VERSION 5.7 ;
BUSBITCHARS "[]" ;
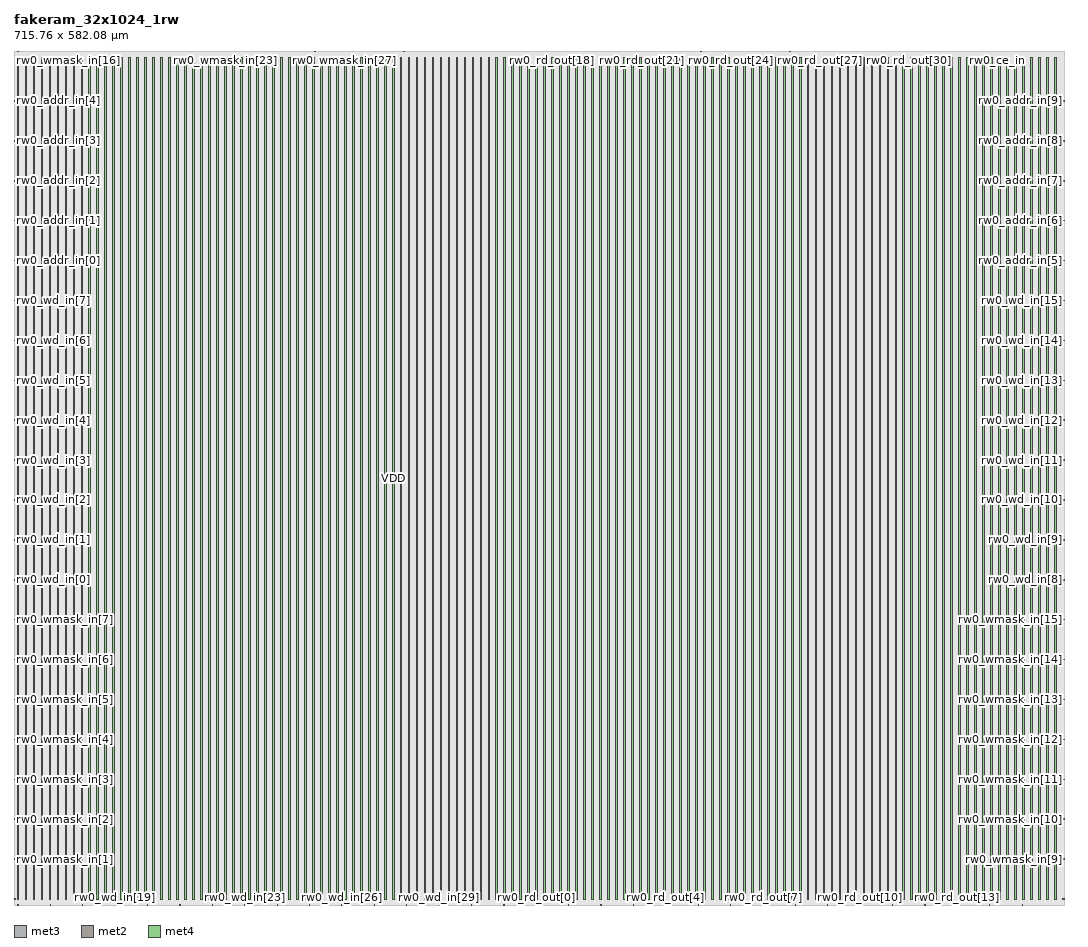
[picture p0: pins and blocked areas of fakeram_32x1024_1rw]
MACRO fakeram_32x1024_1rw
  FOREIGN fakeram_32x1024_1rw 0 0 ;
  SYMMETRY X Y R90 ;
  SIZE 715.760 BY 582.080 ;
  CLASS BLOCK ;
  PIN rw0_wmask_in[0]
    DIRECTION INPUT ;
    USE SIGNAL ;
    SHAPE ABUTMENT ;
    PORT
      LAYER met3 ;
      RECT 0.000 3.930 0.900 4.230 ;
    END
  END rw0_wmask_in[0]
  PIN rw0_wmask_in[1]
    DIRECTION INPUT ;
    USE SIGNAL ;
    SHAPE ABUTMENT ;
    PORT
      LAYER met3 ;
      RECT 0.000 31.130 0.900 31.430 ;
    END
  END rw0_wmask_in[1]
  PIN rw0_wmask_in[2]
    DIRECTION INPUT ;
    USE SIGNAL ;
    SHAPE ABUTMENT ;
    PORT
      LAYER met3 ;
      RECT 0.000 58.330 0.900 58.630 ;
    END
  END rw0_wmask_in[2]
  PIN rw0_wmask_in[3]
    DIRECTION INPUT ;
    USE SIGNAL ;
    SHAPE ABUTMENT ;
    PORT
      LAYER met3 ;
      RECT 0.000 85.530 0.900 85.830 ;
    END
  END rw0_wmask_in[3]
  PIN rw0_wmask_in[4]
    DIRECTION INPUT ;
    USE SIGNAL ;
    SHAPE ABUTMENT ;
    PORT
      LAYER met3 ;
      RECT 0.000 112.730 0.900 113.030 ;
    END
  END rw0_wmask_in[4]
  PIN rw0_wmask_in[5]
    DIRECTION INPUT ;
    USE SIGNAL ;
    SHAPE ABUTMENT ;
    PORT
      LAYER met3 ;
      RECT 0.000 139.930 0.900 140.230 ;
    END
  END rw0_wmask_in[5]
  PIN rw0_wmask_in[6]
    DIRECTION INPUT ;
    USE SIGNAL ;
    SHAPE ABUTMENT ;
    PORT
      LAYER met3 ;
      RECT 0.000 167.130 0.900 167.430 ;
    END
  END rw0_wmask_in[6]
  PIN rw0_wmask_in[7]
    DIRECTION INPUT ;
    USE SIGNAL ;
    SHAPE ABUTMENT ;
    PORT
      LAYER met3 ;
      RECT 0.000 194.330 0.900 194.630 ;
    END
  END rw0_wmask_in[7]
  PIN rw0_wmask_in[8]
    DIRECTION INPUT ;
    USE SIGNAL ;
    SHAPE ABUTMENT ;
    PORT
      LAYER met3 ;
      RECT 714.860 3.930 715.760 4.230 ;
    END
  END rw0_wmask_in[8]
  PIN rw0_wmask_in[9]
    DIRECTION INPUT ;
    USE SIGNAL ;
    SHAPE ABUTMENT ;
    PORT
      LAYER met3 ;
      RECT 714.860 31.130 715.760 31.430 ;
    END
  END rw0_wmask_in[9]
  PIN rw0_wmask_in[10]
    DIRECTION INPUT ;
    USE SIGNAL ;
    SHAPE ABUTMENT ;
    PORT
      LAYER met3 ;
      RECT 714.860 58.330 715.760 58.630 ;
    END
  END rw0_wmask_in[10]
  PIN rw0_wmask_in[11]
    DIRECTION INPUT ;
    USE SIGNAL ;
    SHAPE ABUTMENT ;
    PORT
      LAYER met3 ;
      RECT 714.860 85.530 715.760 85.830 ;
    END
  END rw0_wmask_in[11]
  PIN rw0_wmask_in[12]
    DIRECTION INPUT ;
    USE SIGNAL ;
    SHAPE ABUTMENT ;
    PORT
      LAYER met3 ;
      RECT 714.860 112.730 715.760 113.030 ;
    END
  END rw0_wmask_in[12]
  PIN rw0_wmask_in[13]
    DIRECTION INPUT ;
    USE SIGNAL ;
    SHAPE ABUTMENT ;
    PORT
      LAYER met3 ;
      RECT 714.860 139.930 715.760 140.230 ;
    END
  END rw0_wmask_in[13]
  PIN rw0_wmask_in[14]
    DIRECTION INPUT ;
    USE SIGNAL ;
    SHAPE ABUTMENT ;
    PORT
      LAYER met3 ;
      RECT 714.860 167.130 715.760 167.430 ;
    END
  END rw0_wmask_in[14]
  PIN rw0_wmask_in[15]
    DIRECTION INPUT ;
    USE SIGNAL ;
    SHAPE ABUTMENT ;
    PORT
      LAYER met3 ;
      RECT 714.860 194.330 715.760 194.630 ;
    END
  END rw0_wmask_in[15]
  PIN rw0_wmask_in[16]
    DIRECTION INPUT ;
    USE SIGNAL ;
    SHAPE ABUTMENT ;
    PORT
      LAYER met2 ;
      RECT 2.690 581.660 2.830 582.080 ;
    END
  END rw0_wmask_in[16]
  PIN rw0_wmask_in[17]
    DIRECTION INPUT ;
    USE SIGNAL ;
    SHAPE ABUTMENT ;
    PORT
      LAYER met2 ;
      RECT 22.930 581.660 23.070 582.080 ;
    END
  END rw0_wmask_in[17]
  PIN rw0_wmask_in[18]
    DIRECTION INPUT ;
    USE SIGNAL ;
    SHAPE ABUTMENT ;
    PORT
      LAYER met2 ;
      RECT 43.170 581.660 43.310 582.080 ;
    END
  END rw0_wmask_in[18]
  PIN rw0_wmask_in[19]
    DIRECTION INPUT ;
    USE SIGNAL ;
    SHAPE ABUTMENT ;
    PORT
      LAYER met2 ;
      RECT 63.410 581.660 63.550 582.080 ;
    END
  END rw0_wmask_in[19]
  PIN rw0_wmask_in[20]
    DIRECTION INPUT ;
    USE SIGNAL ;
    SHAPE ABUTMENT ;
    PORT
      LAYER met2 ;
      RECT 83.650 581.660 83.790 582.080 ;
    END
  END rw0_wmask_in[20]
  PIN rw0_wmask_in[21]
    DIRECTION INPUT ;
    USE SIGNAL ;
    SHAPE ABUTMENT ;
    PORT
      LAYER met2 ;
      RECT 103.890 581.660 104.030 582.080 ;
    END
  END rw0_wmask_in[21]
  PIN rw0_wmask_in[22]
    DIRECTION INPUT ;
    USE SIGNAL ;
    SHAPE ABUTMENT ;
    PORT
      LAYER met2 ;
      RECT 124.130 581.660 124.270 582.080 ;
    END
  END rw0_wmask_in[22]
  PIN rw0_wmask_in[23]
    DIRECTION INPUT ;
    USE SIGNAL ;
    SHAPE ABUTMENT ;
    PORT
      LAYER met2 ;
      RECT 144.370 581.660 144.510 582.080 ;
    END
  END rw0_wmask_in[23]
  PIN rw0_wmask_in[24]
    DIRECTION INPUT ;
    USE SIGNAL ;
    SHAPE ABUTMENT ;
    PORT
      LAYER met2 ;
      RECT 164.610 581.660 164.750 582.080 ;
    END
  END rw0_wmask_in[24]
  PIN rw0_wmask_in[25]
    DIRECTION INPUT ;
    USE SIGNAL ;
    SHAPE ABUTMENT ;
    PORT
      LAYER met2 ;
      RECT 184.850 581.660 184.990 582.080 ;
    END
  END rw0_wmask_in[25]
  PIN rw0_wmask_in[26]
    DIRECTION INPUT ;
    USE SIGNAL ;
    SHAPE ABUTMENT ;
    PORT
      LAYER met2 ;
      RECT 205.090 581.660 205.230 582.080 ;
    END
  END rw0_wmask_in[26]
  PIN rw0_wmask_in[27]
    DIRECTION INPUT ;
    USE SIGNAL ;
    SHAPE ABUTMENT ;
    PORT
      LAYER met2 ;
      RECT 225.330 581.660 225.470 582.080 ;
    END
  END rw0_wmask_in[27]
  PIN rw0_wmask_in[28]
    DIRECTION INPUT ;
    USE SIGNAL ;
    SHAPE ABUTMENT ;
    PORT
      LAYER met2 ;
      RECT 245.570 581.660 245.710 582.080 ;
    END
  END rw0_wmask_in[28]
  PIN rw0_wmask_in[29]
    DIRECTION INPUT ;
    USE SIGNAL ;
    SHAPE ABUTMENT ;
    PORT
      LAYER met2 ;
      RECT 265.810 581.660 265.950 582.080 ;
    END
  END rw0_wmask_in[29]
  PIN rw0_wmask_in[30]
    DIRECTION INPUT ;
    USE SIGNAL ;
    SHAPE ABUTMENT ;
    PORT
      LAYER met2 ;
      RECT 286.050 581.660 286.190 582.080 ;
    END
  END rw0_wmask_in[30]
  PIN rw0_wmask_in[31]
    DIRECTION INPUT ;
    USE SIGNAL ;
    SHAPE ABUTMENT ;
    PORT
      LAYER met2 ;
      RECT 306.290 581.660 306.430 582.080 ;
    END
  END rw0_wmask_in[31]
  PIN rw0_wd_in[0]
    DIRECTION INPUT ;
    USE SIGNAL ;
    SHAPE ABUTMENT ;
    PORT
      LAYER met3 ;
      RECT 0.000 221.530 0.900 221.830 ;
    END
  END rw0_wd_in[0]
  PIN rw0_wd_in[1]
    DIRECTION INPUT ;
    USE SIGNAL ;
    SHAPE ABUTMENT ;
    PORT
      LAYER met3 ;
      RECT 0.000 248.730 0.900 249.030 ;
    END
  END rw0_wd_in[1]
  PIN rw0_wd_in[2]
    DIRECTION INPUT ;
    USE SIGNAL ;
    SHAPE ABUTMENT ;
    PORT
      LAYER met3 ;
      RECT 0.000 275.930 0.900 276.230 ;
    END
  END rw0_wd_in[2]
  PIN rw0_wd_in[3]
    DIRECTION INPUT ;
    USE SIGNAL ;
    SHAPE ABUTMENT ;
    PORT
      LAYER met3 ;
      RECT 0.000 303.130 0.900 303.430 ;
    END
  END rw0_wd_in[3]
  PIN rw0_wd_in[4]
    DIRECTION INPUT ;
    USE SIGNAL ;
    SHAPE ABUTMENT ;
    PORT
      LAYER met3 ;
      RECT 0.000 330.330 0.900 330.630 ;
    END
  END rw0_wd_in[4]
  PIN rw0_wd_in[5]
    DIRECTION INPUT ;
    USE SIGNAL ;
    SHAPE ABUTMENT ;
    PORT
      LAYER met3 ;
      RECT 0.000 357.530 0.900 357.830 ;
    END
  END rw0_wd_in[5]
  PIN rw0_wd_in[6]
    DIRECTION INPUT ;
    USE SIGNAL ;
    SHAPE ABUTMENT ;
    PORT
      LAYER met3 ;
      RECT 0.000 384.730 0.900 385.030 ;
    END
  END rw0_wd_in[6]
  PIN rw0_wd_in[7]
    DIRECTION INPUT ;
    USE SIGNAL ;
    SHAPE ABUTMENT ;
    PORT
      LAYER met3 ;
      RECT 0.000 411.930 0.900 412.230 ;
    END
  END rw0_wd_in[7]
  PIN rw0_wd_in[8]
    DIRECTION INPUT ;
    USE SIGNAL ;
    SHAPE ABUTMENT ;
    PORT
      LAYER met3 ;
      RECT 714.860 221.530 715.760 221.830 ;
    END
  END rw0_wd_in[8]
  PIN rw0_wd_in[9]
    DIRECTION INPUT ;
    USE SIGNAL ;
    SHAPE ABUTMENT ;
    PORT
      LAYER met3 ;
      RECT 714.860 248.730 715.760 249.030 ;
    END
  END rw0_wd_in[9]
  PIN rw0_wd_in[10]
    DIRECTION INPUT ;
    USE SIGNAL ;
    SHAPE ABUTMENT ;
    PORT
      LAYER met3 ;
      RECT 714.860 275.930 715.760 276.230 ;
    END
  END rw0_wd_in[10]
  PIN rw0_wd_in[11]
    DIRECTION INPUT ;
    USE SIGNAL ;
    SHAPE ABUTMENT ;
    PORT
      LAYER met3 ;
      RECT 714.860 303.130 715.760 303.430 ;
    END
  END rw0_wd_in[11]
  PIN rw0_wd_in[12]
    DIRECTION INPUT ;
    USE SIGNAL ;
    SHAPE ABUTMENT ;
    PORT
      LAYER met3 ;
      RECT 714.860 330.330 715.760 330.630 ;
    END
  END rw0_wd_in[12]
  PIN rw0_wd_in[13]
    DIRECTION INPUT ;
    USE SIGNAL ;
    SHAPE ABUTMENT ;
    PORT
      LAYER met3 ;
      RECT 714.860 357.530 715.760 357.830 ;
    END
  END rw0_wd_in[13]
  PIN rw0_wd_in[14]
    DIRECTION INPUT ;
    USE SIGNAL ;
    SHAPE ABUTMENT ;
    PORT
      LAYER met3 ;
      RECT 714.860 384.730 715.760 385.030 ;
    END
  END rw0_wd_in[14]
  PIN rw0_wd_in[15]
    DIRECTION INPUT ;
    USE SIGNAL ;
    SHAPE ABUTMENT ;
    PORT
      LAYER met3 ;
      RECT 714.860 411.930 715.760 412.230 ;
    END
  END rw0_wd_in[15]
  PIN rw0_wd_in[16]
    DIRECTION INPUT ;
    USE SIGNAL ;
    SHAPE ABUTMENT ;
    PORT
      LAYER met2 ;
      RECT 2.690 0.000 2.830 0.420 ;
    END
  END rw0_wd_in[16]
  PIN rw0_wd_in[17]
    DIRECTION INPUT ;
    USE SIGNAL ;
    SHAPE ABUTMENT ;
    PORT
      LAYER met2 ;
      RECT 24.770 0.000 24.910 0.420 ;
    END
  END rw0_wd_in[17]
  PIN rw0_wd_in[18]
    DIRECTION INPUT ;
    USE SIGNAL ;
    SHAPE ABUTMENT ;
    PORT
      LAYER met2 ;
      RECT 46.850 0.000 46.990 0.420 ;
    END
  END rw0_wd_in[18]
  PIN rw0_wd_in[19]
    DIRECTION INPUT ;
    USE SIGNAL ;
    SHAPE ABUTMENT ;
    PORT
      LAYER met2 ;
      RECT 68.930 0.000 69.070 0.420 ;
    END
  END rw0_wd_in[19]
  PIN rw0_wd_in[20]
    DIRECTION INPUT ;
    USE SIGNAL ;
    SHAPE ABUTMENT ;
    PORT
      LAYER met2 ;
      RECT 91.010 0.000 91.150 0.420 ;
    END
  END rw0_wd_in[20]
  PIN rw0_wd_in[21]
    DIRECTION INPUT ;
    USE SIGNAL ;
    SHAPE ABUTMENT ;
    PORT
      LAYER met2 ;
      RECT 113.090 0.000 113.230 0.420 ;
    END
  END rw0_wd_in[21]
  PIN rw0_wd_in[22]
    DIRECTION INPUT ;
    USE SIGNAL ;
    SHAPE ABUTMENT ;
    PORT
      LAYER met2 ;
      RECT 135.170 0.000 135.310 0.420 ;
    END
  END rw0_wd_in[22]
  PIN rw0_wd_in[23]
    DIRECTION INPUT ;
    USE SIGNAL ;
    SHAPE ABUTMENT ;
    PORT
      LAYER met2 ;
      RECT 157.250 0.000 157.390 0.420 ;
    END
  END rw0_wd_in[23]
  PIN rw0_wd_in[24]
    DIRECTION INPUT ;
    USE SIGNAL ;
    SHAPE ABUTMENT ;
    PORT
      LAYER met2 ;
      RECT 179.330 0.000 179.470 0.420 ;
    END
  END rw0_wd_in[24]
  PIN rw0_wd_in[25]
    DIRECTION INPUT ;
    USE SIGNAL ;
    SHAPE ABUTMENT ;
    PORT
      LAYER met2 ;
      RECT 201.410 0.000 201.550 0.420 ;
    END
  END rw0_wd_in[25]
  PIN rw0_wd_in[26]
    DIRECTION INPUT ;
    USE SIGNAL ;
    SHAPE ABUTMENT ;
    PORT
      LAYER met2 ;
      RECT 223.490 0.000 223.630 0.420 ;
    END
  END rw0_wd_in[26]
  PIN rw0_wd_in[27]
    DIRECTION INPUT ;
    USE SIGNAL ;
    SHAPE ABUTMENT ;
    PORT
      LAYER met2 ;
      RECT 245.570 0.000 245.710 0.420 ;
    END
  END rw0_wd_in[27]
  PIN rw0_wd_in[28]
    DIRECTION INPUT ;
    USE SIGNAL ;
    SHAPE ABUTMENT ;
    PORT
      LAYER met2 ;
      RECT 267.650 0.000 267.790 0.420 ;
    END
  END rw0_wd_in[28]
  PIN rw0_wd_in[29]
    DIRECTION INPUT ;
    USE SIGNAL ;
    SHAPE ABUTMENT ;
    PORT
      LAYER met2 ;
      RECT 289.730 0.000 289.870 0.420 ;
    END
  END rw0_wd_in[29]
  PIN rw0_wd_in[30]
    DIRECTION INPUT ;
    USE SIGNAL ;
    SHAPE ABUTMENT ;
    PORT
      LAYER met2 ;
      RECT 311.810 0.000 311.950 0.420 ;
    END
  END rw0_wd_in[30]
  PIN rw0_wd_in[31]
    DIRECTION INPUT ;
    USE SIGNAL ;
    SHAPE ABUTMENT ;
    PORT
      LAYER met2 ;
      RECT 333.890 0.000 334.030 0.420 ;
    END
  END rw0_wd_in[31]
  PIN rw0_rd_out[0]
    DIRECTION OUTPUT ;
    USE SIGNAL ;
    SHAPE ABUTMENT ;
    PORT
      LAYER met2 ;
      RECT 355.970 0.000 356.110 0.420 ;
    END
  END rw0_rd_out[0]
  PIN rw0_rd_out[1]
    DIRECTION OUTPUT ;
    USE SIGNAL ;
    SHAPE ABUTMENT ;
    PORT
      LAYER met2 ;
      RECT 378.050 0.000 378.190 0.420 ;
    END
  END rw0_rd_out[1]
  PIN rw0_rd_out[2]
    DIRECTION OUTPUT ;
    USE SIGNAL ;
    SHAPE ABUTMENT ;
    PORT
      LAYER met2 ;
      RECT 400.130 0.000 400.270 0.420 ;
    END
  END rw0_rd_out[2]
  PIN rw0_rd_out[3]
    DIRECTION OUTPUT ;
    USE SIGNAL ;
    SHAPE ABUTMENT ;
    PORT
      LAYER met2 ;
      RECT 422.210 0.000 422.350 0.420 ;
    END
  END rw0_rd_out[3]
  PIN rw0_rd_out[4]
    DIRECTION OUTPUT ;
    USE SIGNAL ;
    SHAPE ABUTMENT ;
    PORT
      LAYER met2 ;
      RECT 444.290 0.000 444.430 0.420 ;
    END
  END rw0_rd_out[4]
  PIN rw0_rd_out[5]
    DIRECTION OUTPUT ;
    USE SIGNAL ;
    SHAPE ABUTMENT ;
    PORT
      LAYER met2 ;
      RECT 466.370 0.000 466.510 0.420 ;
    END
  END rw0_rd_out[5]
  PIN rw0_rd_out[6]
    DIRECTION OUTPUT ;
    USE SIGNAL ;
    SHAPE ABUTMENT ;
    PORT
      LAYER met2 ;
      RECT 488.450 0.000 488.590 0.420 ;
    END
  END rw0_rd_out[6]
  PIN rw0_rd_out[7]
    DIRECTION OUTPUT ;
    USE SIGNAL ;
    SHAPE ABUTMENT ;
    PORT
      LAYER met2 ;
      RECT 510.530 0.000 510.670 0.420 ;
    END
  END rw0_rd_out[7]
  PIN rw0_rd_out[8]
    DIRECTION OUTPUT ;
    USE SIGNAL ;
    SHAPE ABUTMENT ;
    PORT
      LAYER met2 ;
      RECT 532.610 0.000 532.750 0.420 ;
    END
  END rw0_rd_out[8]
  PIN rw0_rd_out[9]
    DIRECTION OUTPUT ;
    USE SIGNAL ;
    SHAPE ABUTMENT ;
    PORT
      LAYER met2 ;
      RECT 554.690 0.000 554.830 0.420 ;
    END
  END rw0_rd_out[9]
  PIN rw0_rd_out[10]
    DIRECTION OUTPUT ;
    USE SIGNAL ;
    SHAPE ABUTMENT ;
    PORT
      LAYER met2 ;
      RECT 576.770 0.000 576.910 0.420 ;
    END
  END rw0_rd_out[10]
  PIN rw0_rd_out[11]
    DIRECTION OUTPUT ;
    USE SIGNAL ;
    SHAPE ABUTMENT ;
    PORT
      LAYER met2 ;
      RECT 598.850 0.000 598.990 0.420 ;
    END
  END rw0_rd_out[11]
  PIN rw0_rd_out[12]
    DIRECTION OUTPUT ;
    USE SIGNAL ;
    SHAPE ABUTMENT ;
    PORT
      LAYER met2 ;
      RECT 620.930 0.000 621.070 0.420 ;
    END
  END rw0_rd_out[12]
  PIN rw0_rd_out[13]
    DIRECTION OUTPUT ;
    USE SIGNAL ;
    SHAPE ABUTMENT ;
    PORT
      LAYER met2 ;
      RECT 643.010 0.000 643.150 0.420 ;
    END
  END rw0_rd_out[13]
  PIN rw0_rd_out[14]
    DIRECTION OUTPUT ;
    USE SIGNAL ;
    SHAPE ABUTMENT ;
    PORT
      LAYER met2 ;
      RECT 665.090 0.000 665.230 0.420 ;
    END
  END rw0_rd_out[14]
  PIN rw0_rd_out[15]
    DIRECTION OUTPUT ;
    USE SIGNAL ;
    SHAPE ABUTMENT ;
    PORT
      LAYER met2 ;
      RECT 687.170 0.000 687.310 0.420 ;
    END
  END rw0_rd_out[15]
  PIN rw0_rd_out[16]
    DIRECTION OUTPUT ;
    USE SIGNAL ;
    SHAPE ABUTMENT ;
    PORT
      LAYER met2 ;
      RECT 326.530 581.660 326.670 582.080 ;
    END
  END rw0_rd_out[16]
  PIN rw0_rd_out[17]
    DIRECTION OUTPUT ;
    USE SIGNAL ;
    SHAPE ABUTMENT ;
    PORT
      LAYER met2 ;
      RECT 346.770 581.660 346.910 582.080 ;
    END
  END rw0_rd_out[17]
  PIN rw0_rd_out[18]
    DIRECTION OUTPUT ;
    USE SIGNAL ;
    SHAPE ABUTMENT ;
    PORT
      LAYER met2 ;
      RECT 367.010 581.660 367.150 582.080 ;
    END
  END rw0_rd_out[18]
  PIN rw0_rd_out[19]
    DIRECTION OUTPUT ;
    USE SIGNAL ;
    SHAPE ABUTMENT ;
    PORT
      LAYER met2 ;
      RECT 387.250 581.660 387.390 582.080 ;
    END
  END rw0_rd_out[19]
  PIN rw0_rd_out[20]
    DIRECTION OUTPUT ;
    USE SIGNAL ;
    SHAPE ABUTMENT ;
    PORT
      LAYER met2 ;
      RECT 407.490 581.660 407.630 582.080 ;
    END
  END rw0_rd_out[20]
  PIN rw0_rd_out[21]
    DIRECTION OUTPUT ;
    USE SIGNAL ;
    SHAPE ABUTMENT ;
    PORT
      LAYER met2 ;
      RECT 427.730 581.660 427.870 582.080 ;
    END
  END rw0_rd_out[21]
  PIN rw0_rd_out[22]
    DIRECTION OUTPUT ;
    USE SIGNAL ;
    SHAPE ABUTMENT ;
    PORT
      LAYER met2 ;
      RECT 447.970 581.660 448.110 582.080 ;
    END
  END rw0_rd_out[22]
  PIN rw0_rd_out[23]
    DIRECTION OUTPUT ;
    USE SIGNAL ;
    SHAPE ABUTMENT ;
    PORT
      LAYER met2 ;
      RECT 468.210 581.660 468.350 582.080 ;
    END
  END rw0_rd_out[23]
  PIN rw0_rd_out[24]
    DIRECTION OUTPUT ;
    USE SIGNAL ;
    SHAPE ABUTMENT ;
    PORT
      LAYER met2 ;
      RECT 488.450 581.660 488.590 582.080 ;
    END
  END rw0_rd_out[24]
  PIN rw0_rd_out[25]
    DIRECTION OUTPUT ;
    USE SIGNAL ;
    SHAPE ABUTMENT ;
    PORT
      LAYER met2 ;
      RECT 508.690 581.660 508.830 582.080 ;
    END
  END rw0_rd_out[25]
  PIN rw0_rd_out[26]
    DIRECTION OUTPUT ;
    USE SIGNAL ;
    SHAPE ABUTMENT ;
    PORT
      LAYER met2 ;
      RECT 528.930 581.660 529.070 582.080 ;
    END
  END rw0_rd_out[26]
  PIN rw0_rd_out[27]
    DIRECTION OUTPUT ;
    USE SIGNAL ;
    SHAPE ABUTMENT ;
    PORT
      LAYER met2 ;
      RECT 549.170 581.660 549.310 582.080 ;
    END
  END rw0_rd_out[27]
  PIN rw0_rd_out[28]
    DIRECTION OUTPUT ;
    USE SIGNAL ;
    SHAPE ABUTMENT ;
    PORT
      LAYER met2 ;
      RECT 569.410 581.660 569.550 582.080 ;
    END
  END rw0_rd_out[28]
  PIN rw0_rd_out[29]
    DIRECTION OUTPUT ;
    USE SIGNAL ;
    SHAPE ABUTMENT ;
    PORT
      LAYER met2 ;
      RECT 589.650 581.660 589.790 582.080 ;
    END
  END rw0_rd_out[29]
  PIN rw0_rd_out[30]
    DIRECTION OUTPUT ;
    USE SIGNAL ;
    SHAPE ABUTMENT ;
    PORT
      LAYER met2 ;
      RECT 609.890 581.660 610.030 582.080 ;
    END
  END rw0_rd_out[30]
  PIN rw0_rd_out[31]
    DIRECTION OUTPUT ;
    USE SIGNAL ;
    SHAPE ABUTMENT ;
    PORT
      LAYER met2 ;
      RECT 630.130 581.660 630.270 582.080 ;
    END
  END rw0_rd_out[31]
  PIN rw0_addr_in[0]
    DIRECTION INPUT ;
    USE SIGNAL ;
    SHAPE ABUTMENT ;
    PORT
      LAYER met3 ;
      RECT 0.000 439.130 0.900 439.430 ;
    END
  END rw0_addr_in[0]
  PIN rw0_addr_in[1]
    DIRECTION INPUT ;
    USE SIGNAL ;
    SHAPE ABUTMENT ;
    PORT
      LAYER met3 ;
      RECT 0.000 466.330 0.900 466.630 ;
    END
  END rw0_addr_in[1]
  PIN rw0_addr_in[2]
    DIRECTION INPUT ;
    USE SIGNAL ;
    SHAPE ABUTMENT ;
    PORT
      LAYER met3 ;
      RECT 0.000 493.530 0.900 493.830 ;
    END
  END rw0_addr_in[2]
  PIN rw0_addr_in[3]
    DIRECTION INPUT ;
    USE SIGNAL ;
    SHAPE ABUTMENT ;
    PORT
      LAYER met3 ;
      RECT 0.000 520.730 0.900 521.030 ;
    END
  END rw0_addr_in[3]
  PIN rw0_addr_in[4]
    DIRECTION INPUT ;
    USE SIGNAL ;
    SHAPE ABUTMENT ;
    PORT
      LAYER met3 ;
      RECT 0.000 547.930 0.900 548.230 ;
    END
  END rw0_addr_in[4]
  PIN rw0_addr_in[5]
    DIRECTION INPUT ;
    USE SIGNAL ;
    SHAPE ABUTMENT ;
    PORT
      LAYER met3 ;
      RECT 714.860 439.130 715.760 439.430 ;
    END
  END rw0_addr_in[5]
  PIN rw0_addr_in[6]
    DIRECTION INPUT ;
    USE SIGNAL ;
    SHAPE ABUTMENT ;
    PORT
      LAYER met3 ;
      RECT 714.860 466.330 715.760 466.630 ;
    END
  END rw0_addr_in[6]
  PIN rw0_addr_in[7]
    DIRECTION INPUT ;
    USE SIGNAL ;
    SHAPE ABUTMENT ;
    PORT
      LAYER met3 ;
      RECT 714.860 493.530 715.760 493.830 ;
    END
  END rw0_addr_in[7]
  PIN rw0_addr_in[8]
    DIRECTION INPUT ;
    USE SIGNAL ;
    SHAPE ABUTMENT ;
    PORT
      LAYER met3 ;
      RECT 714.860 520.730 715.760 521.030 ;
    END
  END rw0_addr_in[8]
  PIN rw0_addr_in[9]
    DIRECTION INPUT ;
    USE SIGNAL ;
    SHAPE ABUTMENT ;
    PORT
      LAYER met3 ;
      RECT 714.860 547.930 715.760 548.230 ;
    END
  END rw0_addr_in[9]
  PIN rw0_we_in
    DIRECTION INPUT ;
    USE SIGNAL ;
    SHAPE ABUTMENT ;
    PORT
      LAYER met2 ;
      RECT 650.370 581.660 650.510 582.080 ;
    END
  END rw0_we_in
  PIN rw0_ce_in
    DIRECTION INPUT ;
    USE SIGNAL ;
    SHAPE ABUTMENT ;
    PORT
      LAYER met2 ;
      RECT 670.610 581.660 670.750 582.080 ;
    END
  END rw0_ce_in
  PIN rw0_clk
    DIRECTION INPUT ;
    USE SIGNAL ;
    SHAPE ABUTMENT ;
    PORT
      LAYER met2 ;
      RECT 690.850 581.660 690.990 582.080 ;
    END
  END rw0_clk
  PIN VSS
    DIRECTION INOUT ;
    USE GROUND ;
    PORT
      LAYER met4 ;
      RECT 2.160 4.080 3.360 578.000 ;
      RECT 13.040 4.080 14.240 578.000 ;
      RECT 23.920 4.080 25.120 578.000 ;
      RECT 34.800 4.080 36.000 578.000 ;
      RECT 45.680 4.080 46.880 578.000 ;
      RECT 56.560 4.080 57.760 578.000 ;
      RECT 67.440 4.080 68.640 578.000 ;
      RECT 78.320 4.080 79.520 578.000 ;
      RECT 89.200 4.080 90.400 578.000 ;
      RECT 100.080 4.080 101.280 578.000 ;
      RECT 110.960 4.080 112.160 578.000 ;
      RECT 121.840 4.080 123.040 578.000 ;
      RECT 132.720 4.080 133.920 578.000 ;
      RECT 143.600 4.080 144.800 578.000 ;
      RECT 154.480 4.080 155.680 578.000 ;
      RECT 165.360 4.080 166.560 578.000 ;
      RECT 176.240 4.080 177.440 578.000 ;
      RECT 187.120 4.080 188.320 578.000 ;
      RECT 198.000 4.080 199.200 578.000 ;
      RECT 208.880 4.080 210.080 578.000 ;
      RECT 219.760 4.080 220.960 578.000 ;
      RECT 230.640 4.080 231.840 578.000 ;
      RECT 241.520 4.080 242.720 578.000 ;
      RECT 252.400 4.080 253.600 578.000 ;
      RECT 263.280 4.080 264.480 578.000 ;
      RECT 274.160 4.080 275.360 578.000 ;
      RECT 285.040 4.080 286.240 578.000 ;
      RECT 295.920 4.080 297.120 578.000 ;
      RECT 306.800 4.080 308.000 578.000 ;
      RECT 317.680 4.080 318.880 578.000 ;
      RECT 328.560 4.080 329.760 578.000 ;
      RECT 339.440 4.080 340.640 578.000 ;
      RECT 350.320 4.080 351.520 578.000 ;
      RECT 361.200 4.080 362.400 578.000 ;
      RECT 372.080 4.080 373.280 578.000 ;
      RECT 382.960 4.080 384.160 578.000 ;
      RECT 393.840 4.080 395.040 578.000 ;
      RECT 404.720 4.080 405.920 578.000 ;
      RECT 415.600 4.080 416.800 578.000 ;
      RECT 426.480 4.080 427.680 578.000 ;
      RECT 437.360 4.080 438.560 578.000 ;
      RECT 448.240 4.080 449.440 578.000 ;
      RECT 459.120 4.080 460.320 578.000 ;
      RECT 470.000 4.080 471.200 578.000 ;
      RECT 480.880 4.080 482.080 578.000 ;
      RECT 491.760 4.080 492.960 578.000 ;
      RECT 502.640 4.080 503.840 578.000 ;
      RECT 513.520 4.080 514.720 578.000 ;
      RECT 524.400 4.080 525.600 578.000 ;
      RECT 535.280 4.080 536.480 578.000 ;
      RECT 546.160 4.080 547.360 578.000 ;
      RECT 557.040 4.080 558.240 578.000 ;
      RECT 567.920 4.080 569.120 578.000 ;
      RECT 578.800 4.080 580.000 578.000 ;
      RECT 589.680 4.080 590.880 578.000 ;
      RECT 600.560 4.080 601.760 578.000 ;
      RECT 611.440 4.080 612.640 578.000 ;
      RECT 622.320 4.080 623.520 578.000 ;
      RECT 633.200 4.080 634.400 578.000 ;
      RECT 644.080 4.080 645.280 578.000 ;
      RECT 654.960 4.080 656.160 578.000 ;
      RECT 665.840 4.080 667.040 578.000 ;
      RECT 676.720 4.080 677.920 578.000 ;
      RECT 687.600 4.080 688.800 578.000 ;
      RECT 698.480 4.080 699.680 578.000 ;
      RECT 709.360 4.080 710.560 578.000 ;
    END
  END VSS
  PIN VDD
    DIRECTION INOUT ;
    USE POWER ;
    PORT
      LAYER met4 ;
      RECT 7.600 4.080 8.800 578.000 ;
      RECT 18.480 4.080 19.680 578.000 ;
      RECT 29.360 4.080 30.560 578.000 ;
      RECT 40.240 4.080 41.440 578.000 ;
      RECT 51.120 4.080 52.320 578.000 ;
      RECT 62.000 4.080 63.200 578.000 ;
      RECT 72.880 4.080 74.080 578.000 ;
      RECT 83.760 4.080 84.960 578.000 ;
      RECT 94.640 4.080 95.840 578.000 ;
      RECT 105.520 4.080 106.720 578.000 ;
      RECT 116.400 4.080 117.600 578.000 ;
      RECT 127.280 4.080 128.480 578.000 ;
      RECT 138.160 4.080 139.360 578.000 ;
      RECT 149.040 4.080 150.240 578.000 ;
      RECT 159.920 4.080 161.120 578.000 ;
      RECT 170.800 4.080 172.000 578.000 ;
      RECT 181.680 4.080 182.880 578.000 ;
      RECT 192.560 4.080 193.760 578.000 ;
      RECT 203.440 4.080 204.640 578.000 ;
      RECT 214.320 4.080 215.520 578.000 ;
      RECT 225.200 4.080 226.400 578.000 ;
      RECT 236.080 4.080 237.280 578.000 ;
      RECT 246.960 4.080 248.160 578.000 ;
      RECT 257.840 4.080 259.040 578.000 ;
      RECT 268.720 4.080 269.920 578.000 ;
      RECT 279.600 4.080 280.800 578.000 ;
      RECT 290.480 4.080 291.680 578.000 ;
      RECT 301.360 4.080 302.560 578.000 ;
      RECT 312.240 4.080 313.440 578.000 ;
      RECT 323.120 4.080 324.320 578.000 ;
      RECT 334.000 4.080 335.200 578.000 ;
      RECT 344.880 4.080 346.080 578.000 ;
      RECT 355.760 4.080 356.960 578.000 ;
      RECT 366.640 4.080 367.840 578.000 ;
      RECT 377.520 4.080 378.720 578.000 ;
      RECT 388.400 4.080 389.600 578.000 ;
      RECT 399.280 4.080 400.480 578.000 ;
      RECT 410.160 4.080 411.360 578.000 ;
      RECT 421.040 4.080 422.240 578.000 ;
      RECT 431.920 4.080 433.120 578.000 ;
      RECT 442.800 4.080 444.000 578.000 ;
      RECT 453.680 4.080 454.880 578.000 ;
      RECT 464.560 4.080 465.760 578.000 ;
      RECT 475.440 4.080 476.640 578.000 ;
      RECT 486.320 4.080 487.520 578.000 ;
      RECT 497.200 4.080 498.400 578.000 ;
      RECT 508.080 4.080 509.280 578.000 ;
      RECT 518.960 4.080 520.160 578.000 ;
      RECT 529.840 4.080 531.040 578.000 ;
      RECT 540.720 4.080 541.920 578.000 ;
      RECT 551.600 4.080 552.800 578.000 ;
      RECT 562.480 4.080 563.680 578.000 ;
      RECT 573.360 4.080 574.560 578.000 ;
      RECT 584.240 4.080 585.440 578.000 ;
      RECT 595.120 4.080 596.320 578.000 ;
      RECT 606.000 4.080 607.200 578.000 ;
      RECT 616.880 4.080 618.080 578.000 ;
      RECT 627.760 4.080 628.960 578.000 ;
      RECT 638.640 4.080 639.840 578.000 ;
      RECT 649.520 4.080 650.720 578.000 ;
      RECT 660.400 4.080 661.600 578.000 ;
      RECT 671.280 4.080 672.480 578.000 ;
      RECT 682.160 4.080 683.360 578.000 ;
      RECT 693.040 4.080 694.240 578.000 ;
      RECT 703.920 4.080 705.120 578.000 ;
    END
  END VDD
  OBS
    LAYER met1 ;
    RECT 0 0 715.760 582.080 ;
    LAYER met2 ;
    RECT 0 0 715.760 582.080 ;
    LAYER met3 ;
    RECT 0 0 715.760 582.080 ;
    LAYER met4 ;
    RECT 0 0 715.760 582.080 ;
  END
END fakeram_32x1024_1rw

END LIBRARY
